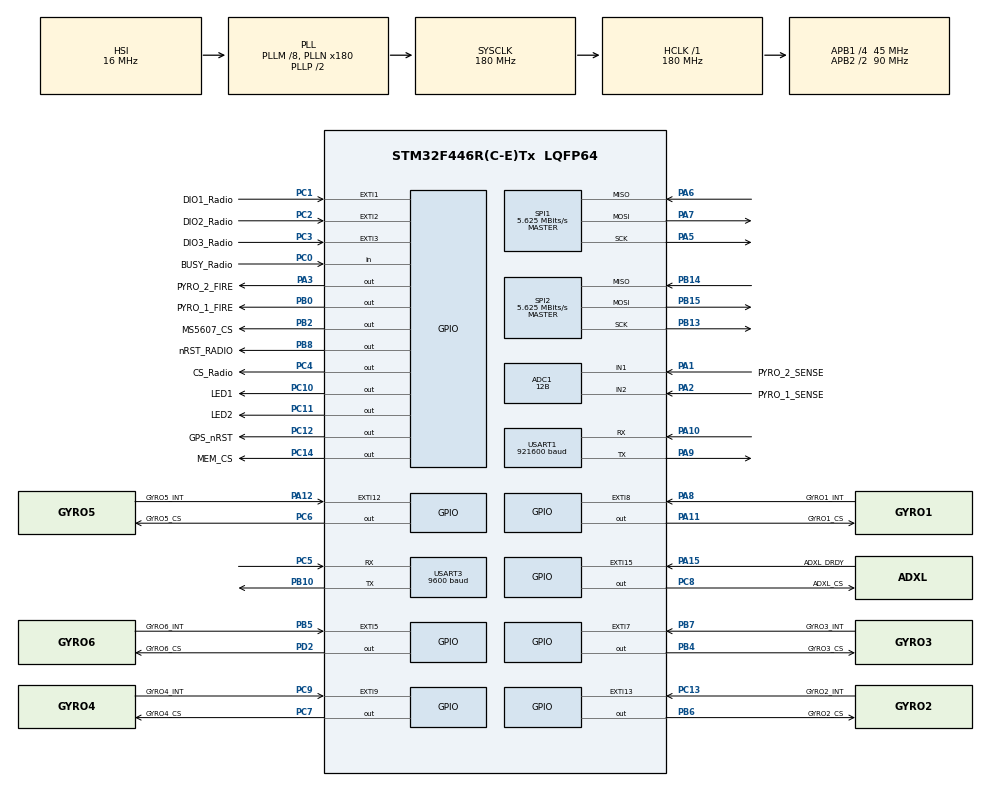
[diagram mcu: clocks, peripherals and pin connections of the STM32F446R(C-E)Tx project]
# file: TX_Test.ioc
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ADC1.Channel-0\#ChannelRegularConversion=ADC_CHANNEL_2
ADC1.ClockPrescaler=ADC_CLOCK_SYNC_PCLK_DIV4
ADC1.ContinuousConvMode=DISABLE
ADC1.DMAContinuousRequests=DISABLE
ADC1.DataAlign=ADC_DATAALIGN_RIGHT
ADC1.DiscontinuousConvMode=DISABLE
ADC1.EOCSelection=ADC_EOC_SINGLE_CONV
ADC1.EnableAnalogWatchDog=false
ADC1.ExternalTrigConv=ADC_SOFTWARE_START
ADC1.ExternalTrigConvEdge=ADC_EXTERNALTRIGCONVEDGE_NONE
ADC1.InjNumberOfConversion=0
ADC1.NbrOfConversion=1
ADC1.NbrOfConversionFlag=1
ADC1.Rank-0\#ChannelRegularConversion=1
ADC1.Resolution=ADC_RESOLUTION_12B
ADC1.SamplingTime-0\#ChannelRegularConversion=ADC_SAMPLETIME_3CYCLES
ADC1.ScanConvMode=DISABLE
ADC1.master=1
Mcu.Family=STM32F4
Mcu.Name=STM32F446R(C-E)Tx
Mcu.Package=LQFP64
NVIC.EXTI15_10_IRQn=true\:1\:0\:true\:false\:true\:true
NVIC.EXTI1_IRQn=true\:1\:0\:true\:false\:true\:true
NVIC.EXTI2_IRQn=true\:1\:0\:true\:false\:true\:true
NVIC.EXTI3_IRQn=true\:1\:0\:true\:false\:true\:true
NVIC.EXTI9_5_IRQn=true\:1\:0\:true\:false\:true\:true
NVIC.PriorityGroup=NVIC_PRIORITYGROUP_4
NVIC.TIM1_UP_TIM10_IRQn=true\:1\:0\:true\:false\:true\:true
NVIC.TIM6_DAC_IRQn=true\:1\:0\:true\:false\:true\:true
NVIC.TIM7_IRQn=true\:1\:0\:true\:false\:true\:true
NVIC.USART1_IRQn=true\:0\:0\:false\:false\:true\:true
NVIC.USART3_IRQn=true\:0\:0\:false\:false\:true\:true
PA1.GPIO_Label=PYRO_2_SENSE
PA1.Signal=ADCx_IN1
PA10.Mode=Asynchronous
PA10.Signal=USART1_RX
PA11.GPIO_Label=GYRO1_CS
PA11.GPIO_Speed=GPIO_SPEED_FREQ_HIGH
PA11.Signal=GPIO_Output
PA12.GPIO_Label=GYRO5_INT
PA12.Signal=GPXTI12
PA13.Mode=Trace_Asynchronous_SW
PA13.Signal=SYS_JTMS-SWDIO
PA14.Mode=Trace_Asynchronous_SW
PA14.Signal=SYS_JTCK-SWCLK
PA15.GPIO_Label=ADXL_DRDY
PA15.Signal=GPXTI15
PA2.GPIO_Label=PYRO_1_SENSE
PA2.Signal=ADCx_IN2
PA3.GPIO_Label=PYRO_2_FIRE
PA3.Signal=GPIO_Output
PA5.Mode=Full_Duplex_Master
PA5.Signal=SPI1_SCK
PA6.Mode=Full_Duplex_Master
PA6.Signal=SPI1_MISO
PA7.Mode=Full_Duplex_Master
PA7.Signal=SPI1_MOSI
PA8.GPIO_Label=GYRO1_INT
PA8.Signal=GPXTI8
PA9.Mode=Asynchronous
PA9.Signal=USART1_TX
PB0.GPIO_Label=PYRO_1_FIRE
PB0.Signal=GPIO_Output
PB10.Mode=Asynchronous
PB10.Signal=USART3_TX
PB13.Mode=Full_Duplex_Master
PB13.Signal=SPI2_SCK
PB14.Mode=Full_Duplex_Master
PB14.Signal=SPI2_MISO
PB15.Mode=Full_Duplex_Master
PB15.Signal=SPI2_MOSI
PB2.GPIO_Label=MS5607_CS
PB2.GPIO_Speed=GPIO_SPEED_FREQ_HIGH
PB2.Signal=GPIO_Output
PB3.Mode=Trace_Asynchronous_SW
PB3.Signal=SYS_JTDO-SWO
PB4.GPIO_Label=GYRO3_CS
PB4.GPIO_Speed=GPIO_SPEED_FREQ_HIGH
PB4.Signal=GPIO_Output
PB5.GPIO_Label=GYRO6_INT
PB5.Signal=GPXTI5
PB6.GPIO_Label=GYRO2_CS
PB6.GPIO_Speed=GPIO_SPEED_FREQ_HIGH
PB6.Signal=GPIO_Output
PB7.GPIO_Label=GYRO3_INT
PB7.Signal=GPXTI7
PB8.GPIO_Label=nRST_RADIO
PB8.Signal=GPIO_Output
PC0.GPIO_Label=BUSY_Radio
PC0.Signal=GPIO_Input
PC1.GPIO_Label=DIO1_Radio
PC1.Signal=GPXTI1
PC10.GPIO_Label=LED1
PC10.Signal=GPIO_Output
PC11.GPIO_Label=LED2
PC11.Signal=GPIO_Output
PC12.GPIO_Label=GPS_nRST
PC12.Signal=GPIO_Output
PC13.GPIO_Label=GYRO2_INT
PC13.Signal=GPXTI13
PC14-OSC32_IN.GPIO_Label=MEM_CS
PC14-OSC32_IN.GPIO_Speed=GPIO_SPEED_FREQ_LOW
PC14-OSC32_IN.Signal=GPIO_Output
PC2.GPIO_Label=DIO2_Radio
PC2.Signal=GPXTI2
PC3.GPIO_Label=DIO3_Radio
PC3.Signal=GPXTI3
PC4.GPIO_Label=CS_Radio
PC4.Signal=GPIO_Output
PC5.Mode=Asynchronous
PC5.Signal=USART3_RX
PC6.GPIO_Label=GYRO5_CS
PC6.GPIO_Speed=GPIO_SPEED_FREQ_HIGH
PC6.Signal=GPIO_Output
PC7.GPIO_Label=GYRO4_CS
PC7.GPIO_Speed=GPIO_SPEED_FREQ_HIGH
PC7.Signal=GPIO_Output
PC8.GPIO_Label=ADXL_CS
PC8.GPIO_Speed=GPIO_SPEED_FREQ_HIGH
PC8.Signal=GPIO_Output
PC9.GPIO_Label=GYRO4_INT
PC9.Signal=GPXTI9
PD2.GPIO_Label=GYRO6_CS
PD2.GPIO_Speed=GPIO_SPEED_FREQ_HIGH
PD2.Signal=GPIO_Output
ProjectManager.HeapSize=0x200
ProjectManager.StackSize=0x400
ProjectManager.TargetToolchain=TrueSTUDIO
RCC.AHBFreq_Value=180000000
RCC.APB1CLKDivider=RCC_HCLK_DIV4
RCC.APB1Freq_Value=45000000
RCC.APB1TimFreq_Value=90000000
RCC.APB2CLKDivider=RCC_HCLK_DIV2
RCC.APB2Freq_Value=90000000
RCC.APB2TimFreq_Value=180000000
RCC.CortexFreq_Value=180000000
RCC.HCLKFreq_Value=180000000
RCC.PLLM=8
RCC.PLLN=180
RCC.SYSCLKFreq_VALUE=180000000
RCC.SYSCLKSource=RCC_SYSCLKSOURCE_PLLCLK
RCC.USBFreq_Value=180000000
RCC.VCOOutputFreq_Value=360000000
SH.ADCx_IN1.0=ADC1_IN1,IN1
SH.ADCx_IN2.0=ADC1_IN2,IN2
SPI1.BaudRatePrescaler=SPI_BAUDRATEPRESCALER_16
SPI1.CalculateBaudRate=5.625 MBits/s
SPI1.Direction=SPI_DIRECTION_2LINES
SPI1.Mode=SPI_MODE_MASTER
SPI1.VirtualType=VM_MASTER
SPI2.BaudRatePrescaler=SPI_BAUDRATEPRESCALER_8
SPI2.CalculateBaudRate=5.625 MBits/s
SPI2.Direction=SPI_DIRECTION_2LINES
SPI2.Mode=SPI_MODE_MASTER
SPI2.VirtualType=VM_MASTER
TIM10.Period=999
TIM10.Prescaler=1799
TIM6.Period=99
TIM6.Prescaler=17999
TIM7.Period=499
TIM7.Prescaler=1799
USART1.BaudRate=921600
USART1.VirtualMode=VM_ASYNC
USART3.BaudRate=9600
USART3.VirtualMode=VM_ASYNC
VP_TIM10_VS_ClockSourceINT.Mode=Enable_Timer
VP_TIM6_VS_ClockSourceINT.Mode=Enable_Timer
VP_TIM7_VS_ClockSourceINT.Mode=Enable_Timer
board=TX_Test

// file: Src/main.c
/**
  ******************************************************************************
  * File Name          : main.c
  * Description        : Main program body
  ******************************************************************************
  ** This notice applies to any and all portions of this file
  * that are not between comment pairs USER CODE BEGIN and
  * USER CODE END. Other portions of this file, whether
  * inserted by the user or by software development tools
  * are owned by their respective copyright owners.
  *
  * COPYRIGHT(c) 2018 STMicroelectronics
  *
  * Redistribution and use in source and binary forms, with or without modification,
  * are permitted provided that the following conditions are met:
  *   1. Redistributions of source code must retain the above copyright notice,
  *      this list of conditions and the following disclaimer.
  *   2. Redistributions in binary form must reproduce the above copyright notice,
  *      this list of conditions and the following disclaimer in the documentation
  *      and/or other materials provided with the distribution.
  *   3. Neither the name of STMicroelectronics nor the names of its contributors
  *      may be used to endorse or promote products derived from this software
  *      without specific prior written permission.
  *
  * THIS SOFTWARE IS PROVIDED BY THE COPYRIGHT HOLDERS AND CONTRIBUTORS "AS IS"
  * AND ANY EXPRESS OR IMPLIED WARRANTIES, INCLUDING, BUT NOT LIMITED TO, THE
  * IMPLIED WARRANTIES OF MERCHANTABILITY AND FITNESS FOR A PARTICULAR PURPOSE ARE
  * DISCLAIMED. IN NO EVENT SHALL THE COPYRIGHT HOLDER OR CONTRIBUTORS BE LIABLE
  * FOR ANY DIRECT, INDIRECT, INCIDENTAL, SPECIAL, EXEMPLARY, OR CONSEQUENTIAL
  * DAMAGES (INCLUDING, BUT NOT LIMITED TO, PROCUREMENT OF SUBSTITUTE GOODS OR
  * SERVICES; LOSS OF USE, DATA, OR PROFITS; OR BUSINESS INTERRUPTION) HOWEVER
  * CAUSED AND ON ANY THEORY OF LIABILITY, WHETHER IN CONTRACT, STRICT LIABILITY,
  * OR TORT (INCLUDING NEGLIGENCE OR OTHERWISE) ARISING IN ANY WAY OUT OF THE USE
  * OF THIS SOFTWARE, EVEN IF ADVISED OF THE POSSIBILITY OF SUCH DAMAGE.
  *
  ******************************************************************************
  */

#include "main.h"
#include "stm32f4xx_hal.h"

/* USER CODE BEGIN Includes */

/*
                                                                   `-/+osyhdmmNNy`
                                                             `-/shmNmhyso+/oMMMy`
                                                         `-+hmNdy+:.`     /mMNo`
                                                     `.:smNds/.`        .yNMm:
                                             `.:+oosmmNmy+.`          .sNMNo`
                                        `-/syhs+:./hmy/`    `::     .odmms.
       ./oyyyo:`       ./oyyy+-      ./ymNyo+oo+/:+/.    ./o//+++//+oso+o++:       .:/++/:.
      :mNNNNNNNh-     /mNNNNNNmy. -odNMMN++dmmdhddd/ `:odNs/hydddmNmdddmmmmo      /ddmmmmdh/
      hNNNmsmNNNm-    hNNNmsmNNms.dNMMMM/-mNdyydmmdd-sNMMh-Ndmmmysossssssss/     -dmmmdhmmmd-
      hNNNh :NNNNh`   hNNNy /NNmm/-+oo++.dNNdd-:dmNNd-NMMo+mddd:                `ymmmd:-dmmmh`
      hNNNh  oNNNN/   hNNNy .omNNm.ddhy-+mNNNo.:sMNNNo+MN/-dmmmho+++++++/-`     +mmmmo  ommmmo
      hNNNh  `dNNNd`  hNNNy-d-dNNm/.-...dhNNh` y.mNNNN-o.  +dmmmmmmmmmmmmmh:   -dmmmh`  `hmmmd-
      hNNNh   :NNNN/  hNmmy:Ms/mdhh.:.`omdmh- .Ny:NNNdy     .+syyyyyyyydmmmd- `ymmmm:    -dmmmy`
      hNNNh    hNNNd` hmNNy:Nh.syss/``+ddmho-:mMM:odmmm/               :mmmmo /mmmmo      ommmm/
      hNNNh    -NNNNy:dmNNy:mms:yoos-.hmmdd-mMNd+.`dmmmd`  .////////::/smmmm/.dmmmh`      `hmmmd.
      hNNNh     +mNNNNNmNm+/yso.odmmyyNddN:sdo-    :mmmms  +mmmmmmmdymmmmmmo`smmmm:        -dmmms
      sddds      -ohdddhs+sdNNMy:dsyhhyydo`-        ohhhh. /hhhhhhysshhhyo- .yhhho          +yyyy.
                    ``` :NMMMMMMh:   .:`                      `.+s.
                         /mMMMMMMs                         `./hmy-
                          .omMMMMMs.`                  `./sdNNy:
                          .-./smNMMMmho+:-..``...-:/oshmMMNmo.
                           :yhysoyNMMMMMMMMMMMMMMMMMMMMNdo-
                             .+ymMMMMMMMMMMMMMMMMMMmyo:`
                                 .-+osyyhhhyyso+:.`
 */

#include "flash.h"
#include "sensors.h"
#include "commandline.h"
#include "GPS.h"
#include "radio.h"
/* USER CODE END Includes */

ADC_HandleTypeDef hadc1;

SPI_HandleTypeDef hspi1;
SPI_HandleTypeDef hspi2;

TIM_HandleTypeDef htim6;
TIM_HandleTypeDef htim7;
TIM_HandleTypeDef htim10;

UART_HandleTypeDef huart1;
UART_HandleTypeDef huart3;

/* USER CODE BEGIN PV */
/* Private variables ---------------------------------------------------------*/

//GLOBALS:
//UART Buffers
uint8_t uart1_in;
buffer uart1_buf;
uint8_t uart3_in;
buffer uart3_buf;
uint16_t packet_number = 0;

union flt{
  float f;
  uint8_t bytes[4];
};
union flt float_conv;

//Sensors Structs
baro b;
gyro gyros[6];
accel a;
extern gps_data gps;
uint32_t last_time = 0;
volatile uint8_t LOGGING_ACTIVE = 0;
uint8_t RX_PARITY = 0;
file* logfile;

//Global Flags
volatile uint8_t ADXL_Log, GYRO1_Log, GYRO2_Log, GYRO3_Log, GYRO4_Log, GYRO5_Log, GYRO6_Log, GPS_Log;
uint8_t radio_tim, baro_tim, ms_tim;
uint8_t baro_conv_state = 0;
uint8_t transmitting = 0;
/* USER CODE END PV */

void SystemClock_Config(void);
static void MX_GPIO_Init(void);
static void MX_ADC1_Init(void);
static void MX_SPI1_Init(void);
static void MX_SPI2_Init(void);
static void MX_TIM10_Init(void);
static void MX_USART1_UART_Init(void);
static void MX_USART3_UART_Init(void);
static void MX_TIM6_Init(void);
static void MX_TIM7_Init(void);

/* USER CODE BEGIN PFP */
/* Private function prototypes -----------------------------------------------*/

/* USER CODE END PFP */

int main(void)
{

  /* USER CODE BEGIN 1 */

  // Initialize uart command buffer

  /* USER CODE END 1 */

  /* MCU Configuration----------------------------------------------------------*/

  /* Reset of all peripherals, Initializes the Flash interface and the Systick. */
  HAL_Init();

  /* Configure the system clock */
  SystemClock_Config();

  /* Initialize all configured peripherals */
  MX_GPIO_Init();
  MX_ADC1_Init();
  MX_SPI1_Init();
  MX_SPI2_Init();
  MX_TIM10_Init();
  MX_USART1_UART_Init();
  MX_USART3_UART_Init();
  MX_TIM6_Init();
  MX_TIM7_Init();

  /* USER CODE BEGIN 2 */
  //Local vars
  volatile uint8_t temp_packet[23] = {0};
  volatile uint8_t radio_status;
  uint8_t radio_tim_count = 0;
  uint8_t tx_clear = 1;
  uint8_t RXData[25] = {0};
  uint8_t TXData[25] = {0};
  uint8_t status_Byte = 0;

  //Init CS pins to default state
  HAL_GPIO_WritePin(GYRO1_CS_GPIO_Port, GYRO1_CS_Pin, 1);
  HAL_GPIO_WritePin(GYRO2_CS_GPIO_Port, GYRO2_CS_Pin, 1);
  HAL_GPIO_WritePin(GYRO3_CS_GPIO_Port, GYRO3_CS_Pin, 1);
  HAL_GPIO_WritePin(GYRO4_CS_GPIO_Port, GYRO4_CS_Pin, 1);
  HAL_GPIO_WritePin(GYRO5_CS_GPIO_Port, GYRO5_CS_Pin, 1);
  HAL_GPIO_WritePin(GYRO6_CS_GPIO_Port, GYRO6_CS_Pin, 1);
  HAL_GPIO_WritePin(MS5607_CS_GPIO_Port, MS5607_CS_Pin, 1);
  HAL_GPIO_WritePin(ADXL_CS_GPIO_Port, ADXL_CS_Pin, 1);
  HAL_GPIO_WritePin(GPS_nRST_GPIO_Port, GPS_nRST_Pin, 1);
  HAL_GPIO_WritePin(MEM_CS_GPIO_Port, MEM_CS_Pin, 1);
  HAL_GPIO_WritePin(RADIO_CS_GPIO_Port, RADIO_CS_Pin, 1);

  unlock_all(); // Flash init

  //Cmd Interface Init
  buffer_init(&uart1_buf, UART_BUFFER_SIZE, 1);
  HAL_UART_Receive_IT(&huart1, &uart1_in, 1);

  //GPS UART Init
  buffer_init(&uart3_buf, UART_BUFFER_SIZE, 3);
  HAL_UART_Receive_IT(&huart3, &uart3_in, 1);

  //Gyro Init
  init_gyros();
  for(int n = 1; n <= 6; n++){
      gyros[n-1].id = n;
  }

  //Accel Init
  init_accel();

  //Baro Init
  init_baro(&b);
  D2_conv_baro(&b);
  HAL_Delay(20);

  //Radio Init
  init_radio();
  radio_resetFIFO();
  radio_initInterrupt();

  print("System Initilization Complete\n\0");

//  for(int i = 0; i<600; i++){
//      read_gyro(&gyros[0]);
//      read_accel(&a);
//      log_accel(logfile, &a);
//      log_gyro(logfile, &gyros[0]);
//      HAL_Delay(5);
//  }
//  close_log(logfile);

  //Start Timers
  HAL_TIM_Base_Init(&htim6);
  HAL_TIM_Base_Start_IT(&htim6);
  HAL_TIM_Base_Init(&htim7);
  HAL_TIM_Base_Start_IT(&htim7);
  HAL_TIM_Base_Init(&htim10);
  HAL_TIM_Base_Start_IT(&htim10);

  /* USER CODE END 2 */

  /* Infinite loop */
  while (1)
  {

  /* USER CODE BEGIN 3 */

	  parse_buffer(&uart1_buf);

	  if(HAL_GetTick() != last_time){
		  if(LOGGING_ACTIVE == 1){
			  last_time = HAL_GetTick();
			  log_time(logfile, last_time);
		  }
	  }
    //Check if a drdy interrupt has occured and fetch data
    if(ADXL_Log == 1){
        read_accel(&a);
        if(LOGGING_ACTIVE == 1){
        	 log_accel(logfile, &a);
        }
        ADXL_Log = 0;
    }
    if(GYRO1_Log == 1){
      read_gyro(&gyros[0]);
      if(LOGGING_ACTIVE == 1){
    	  log_gyro(logfile, &gyros[0]);
	  }
      GYRO1_Log = 0;
    }
    if(GYRO2_Log == 1){
      read_gyro(&gyros[1]);
      if(LOGGING_ACTIVE == 1){
		  log_gyro(logfile, &gyros[1]);
	  }
      GYRO2_Log = 0;
    }
    if(GYRO3_Log == 1){
      read_gyro(&gyros[2]);
      if(LOGGING_ACTIVE == 1){
		  log_gyro(logfile, &gyros[2]);
	  }
      GYRO3_Log = 0;
    }
    if(GYRO4_Log == 1){
      read_gyro(&gyros[3]);
      if(LOGGING_ACTIVE == 1){
		  log_gyro(logfile, &gyros[3]);
	  }
      GYRO4_Log = 0;
    }
    if(GYRO5_Log == 1){
      read_gyro(&gyros[4]);
      if(LOGGING_ACTIVE == 1){
		  log_gyro(logfile, &gyros[4]);
	  }
      GYRO5_Log = 0;
    }
    if(GYRO6_Log == 1){
      read_gyro(&gyros[5]);
      if(LOGGING_ACTIVE == 1){
		  log_gyro(logfile, &gyros[5]);
	  }
      GYRO6_Log = 0;
    }
    if(GPS_Log == 1){
    	if(LOGGING_ACTIVE == 1){
    		log_gps(logfile, &gps);
    	}
        GPS_Log = 0;
    }

    //Check timer interrupts
    if(radio_tim == 1){

        //If we are on a multiple of 10, transmitt a packet
        if(radio_tim_count == 0 || radio_tim_count == 20 || radio_tim_count == 40 || radio_tim_count == 60 || radio_tim_count == 80){

        	if(tx_clear){
        	//Send out radio packet

        		// Build status byte
        		status_Byte = 0;	// Reset
        		status_Byte |= LOGGING_ACTIVE << 7;
        		status_Byte |= RX_PARITY << 6;

        		//

			  temp_packet[1] = status_Byte; //0x0 wil be normal packet
			  temp_packet[2] = (packet_number & 0xFF);
			  temp_packet[3] = (packet_number >> 8) & 0xFF;

			  float_conv.f = gps.latitude;
			  temp_packet[4] = float_conv.bytes[0];
			  temp_packet[5] = float_conv.bytes[1];
			  temp_packet[6] = float_conv.bytes[2];
			  temp_packet[7] = float_conv.bytes[3];

			  float_conv.f = gps.longitude;
			  temp_packet[8] = float_conv.bytes[0];
			  temp_packet[9] = float_conv.bytes[1];
			  temp_packet[10] = float_conv.bytes[2];
			  temp_packet[11] = float_conv.bytes[3];

			  //Need to write function to actually get baro_alt
			  temp_packet[12] = (b.altitude) & 0xFF;
			  temp_packet[13] = (b.altitude >> 8) & 0xFF;

			  //Same as above
	  //        temp_packet[14] = (max_alt >> 8) & 0xFF;
	  //        temp_packet[15] = (max_alt) & 0xFF;

			  //Just send gyro 2 data for now. Can send avg of all channels if wanted
			  //Need to change axis to the correct one...
			  temp_packet[16] = (gyros[2].data[2]) & 0xFF;
			  temp_packet[17] = (gyros[2].data[2] >> 8) & 0xFF;

			  //Need to write function to actually calculate vel from accel
	  //        temp_packet[18] = (gyros[1].data[1] >> 8) & 0xFF;
	  //        temp_packet[19] = (gyros[1].data[1]) & 0xFF;

			  //Need to change axis to the correct one...
			  temp_packet[20] = (a.data[2]) & 0xFF;
			  temp_packet[21] = (a.data[2] >> 8) & 0xFF;
			  temp_packet[22] = (a.data[2] >> 16) & 0xFF;

			  //Do steps for transmit
			  radio_txPacket(temp_packet);
			  packet_number += 1;
        	}
        }
        else if(radio_tim_count == 10 || radio_tim_count == 30 || radio_tim_count == 50 || radio_tim_count == 70 || radio_tim_count == 90){
        	radio_RXMode();
        }
        else if(radio_tim_count == 19 || radio_tim_count == 39 || radio_tim_count == 59 || radio_tim_count == 79 || radio_tim_count == 99){
				  //read packet
				  TXData[0] = 0x7F;
				  TXData[1] = 0x00;
				  HAL_GPIO_WritePin(RADIO_CS_GPIO_Port, RADIO_CS_Pin, 0);
				  HAL_SPI_TransmitReceive(&hspi1, TXData, RXData, 3, 0xff);
				  HAL_GPIO_WritePin(RADIO_CS_GPIO_Port, RADIO_CS_Pin, 1);

				  //This is jank af because it relies on how the radio fifo handles underflow
				  //If there actually wasn't a packet received, RXData[1] and RXData[2] will be the same
				  //But if there was, the command is setup so they will add to get 255
				  //Don't use 128/127 as commands
				  if(RXData[1] + RXData[2] == 0xFF){
					//Valid command received in RXData[1]
					//Tabbing in the document is absolutly fucked

					  RX_PARITY = (RX_PARITY == 0) ? 1 : 0;
					  //Where to define commands??
					  //They are in radio.h at the moment
					  if(RXData[1] == START_LOG){
						//Start the logging
						  if(LOGGING_ACTIVE == 0){
							  logfile = new_log();
						  }
						//Set MSB of status byte to indicate logging is on

					  }
					  else if(RXData[1] == STOP_LOG){
						//Stop the logging
						if(LOGGING_ACTIVE == 1){
							close_log(logfile);
						}
						//Reset MSB of status byte to indicate logging is off

					  }
					  else if(RXData[1] == CLEAR_FILE_SYS){
						//Clear the file system
						init_fs();
					  }
				  }
				  tx_clear = 1;
				  radio_IDLEMode();
		  }

        //radio_status = RADIO_TRANSMITTING;
        radio_tim = 0;
        radio_tim_count += 1;
        if(radio_tim_count >= 100){
            radio_tim_count = 0;
        }
    }
    if(baro_tim == 1){
        //Send conversion and/or read adc
        if(baro_conv_state == 0){
            read_D2_baro(&b);
            D1_conv_baro(&b);
            baro_conv_state = 1;
        }
        else{
            read_D1_baro(&b);
            D2_conv_baro(&b);
            conv_pres_baro(&b);
            conv_alt(&b);
            if(LOGGING_ACTIVE == 1){
            	log_baro(logfile, &b);
            }
            baro_conv_state = 0;
        }
        baro_tim = 0;

        //Use this interrupt to also update radio status
        //If radio pkt sent flag is high, then radio is in IDLE
        if((radio_readInterrupt() & 0b100) != 0){
            radio_status = RADIO_IDLE;
        }
    }
  }
  /* USER CODE END 3 */

}

/** System Clock Configuration
*/
void SystemClock_Config(void)
{

  RCC_OscInitTypeDef RCC_OscInitStruct;
  RCC_ClkInitTypeDef RCC_ClkInitStruct;

    /**Configure the main internal regulator output voltage
    */
  __HAL_RCC_PWR_CLK_ENABLE();

  __HAL_PWR_VOLTAGESCALING_CONFIG(PWR_REGULATOR_VOLTAGE_SCALE1);

    /**Initializes the CPU, AHB and APB busses clocks
    */
  RCC_OscInitStruct.OscillatorType = RCC_OSCILLATORTYPE_HSI;
  RCC_OscInitStruct.HSIState = RCC_HSI_ON;
  RCC_OscInitStruct.HSICalibrationValue = 16;
  RCC_OscInitStruct.PLL.PLLState = RCC_PLL_ON;
  RCC_OscInitStruct.PLL.PLLSource = RCC_PLLSOURCE_HSI;
  RCC_OscInitStruct.PLL.PLLM = 8;
  RCC_OscInitStruct.PLL.PLLN = 180;
  RCC_OscInitStruct.PLL.PLLP = RCC_PLLP_DIV2;
  RCC_OscInitStruct.PLL.PLLQ = 2;
  RCC_OscInitStruct.PLL.PLLR = 2;
  if (HAL_RCC_OscConfig(&RCC_OscInitStruct) != HAL_OK)
  {
    _Error_Handler(__FILE__, __LINE__);
  }

    /**Activate the Over-Drive mode
    */
  if (HAL_PWREx_EnableOverDrive() != HAL_OK)
  {
    _Error_Handler(__FILE__, __LINE__);
  }

    /**Initializes the CPU, AHB and APB busses clocks
    */
  RCC_ClkInitStruct.ClockType = RCC_CLOCKTYPE_HCLK|RCC_CLOCKTYPE_SYSCLK
                              |RCC_CLOCKTYPE_PCLK1|RCC_CLOCKTYPE_PCLK2;
  RCC_ClkInitStruct.SYSCLKSource = RCC_SYSCLKSOURCE_PLLCLK;
  RCC_ClkInitStruct.AHBCLKDivider = RCC_SYSCLK_DIV1;
  RCC_ClkInitStruct.APB1CLKDivider = RCC_HCLK_DIV4;
  RCC_ClkInitStruct.APB2CLKDivider = RCC_HCLK_DIV2;

  if (HAL_RCC_ClockConfig(&RCC_ClkInitStruct, FLASH_LATENCY_5) != HAL_OK)
  {
    _Error_Handler(__FILE__, __LINE__);
  }

    /**Configure the Systick interrupt time
    */
  HAL_SYSTICK_Config(HAL_RCC_GetHCLKFreq()/1000);

    /**Configure the Systick
    */
  HAL_SYSTICK_CLKSourceConfig(SYSTICK_CLKSOURCE_HCLK);

  /* SysTick_IRQn interrupt configuration */
  HAL_NVIC_SetPriority(SysTick_IRQn, 0, 0);
}

/* ADC1 init function */
static void MX_ADC1_Init(void)
{

  ADC_ChannelConfTypeDef sConfig;

    /**Configure the global features of the ADC (Clock, Resolution, Data Alignment and number of conversion)
    */
  hadc1.Instance = ADC1;
  hadc1.Init.ClockPrescaler = ADC_CLOCK_SYNC_PCLK_DIV4;
  hadc1.Init.Resolution = ADC_RESOLUTION_12B;
  hadc1.Init.ScanConvMode = DISABLE;
  hadc1.Init.ContinuousConvMode = DISABLE;
  hadc1.Init.DiscontinuousConvMode = DISABLE;
  hadc1.Init.ExternalTrigConvEdge = ADC_EXTERNALTRIGCONVEDGE_NONE;
  hadc1.Init.ExternalTrigConv = ADC_SOFTWARE_START;
  hadc1.Init.DataAlign = ADC_DATAALIGN_RIGHT;
  hadc1.Init.NbrOfConversion = 1;
  hadc1.Init.DMAContinuousRequests = DISABLE;
  hadc1.Init.EOCSelection = ADC_EOC_SINGLE_CONV;
  if (HAL_ADC_Init(&hadc1) != HAL_OK)
  {
    _Error_Handler(__FILE__, __LINE__);
  }

    /**Configure for the selected ADC regular channel its corresponding rank in the sequencer and its sample time.
    */
  sConfig.Channel = ADC_CHANNEL_2;
  sConfig.Rank = 1;
  sConfig.SamplingTime = ADC_SAMPLETIME_3CYCLES;
  if (HAL_ADC_ConfigChannel(&hadc1, &sConfig) != HAL_OK)
  {
    _Error_Handler(__FILE__, __LINE__);
  }

}

/* SPI1 init function */
static void MX_SPI1_Init(void)
{

  /* SPI1 parameter configuration*/
  hspi1.Instance = SPI1;
  hspi1.Init.Mode = SPI_MODE_MASTER;
  hspi1.Init.Direction = SPI_DIRECTION_2LINES;
  hspi1.Init.DataSize = SPI_DATASIZE_8BIT;
  hspi1.Init.CLKPolarity = SPI_POLARITY_LOW;
  hspi1.Init.CLKPhase = SPI_PHASE_1EDGE;
  hspi1.Init.NSS = SPI_NSS_SOFT;
  hspi1.Init.BaudRatePrescaler = SPI_BAUDRATEPRESCALER_16;
  hspi1.Init.FirstBit = SPI_FIRSTBIT_MSB;
  hspi1.Init.TIMode = SPI_TIMODE_DISABLE;
  hspi1.Init.CRCCalculation = SPI_CRCCALCULATION_DISABLE;
  hspi1.Init.CRCPolynomial = 10;
  if (HAL_SPI_Init(&hspi1) != HAL_OK)
  {
    _Error_Handler(__FILE__, __LINE__);
  }

}

/* SPI2 init function */
static void MX_SPI2_Init(void)
{

  /* SPI2 parameter configuration*/
  hspi2.Instance = SPI2;
  hspi2.Init.Mode = SPI_MODE_MASTER;
  hspi2.Init.Direction = SPI_DIRECTION_2LINES;
  hspi2.Init.DataSize = SPI_DATASIZE_8BIT;
  hspi2.Init.CLKPolarity = SPI_POLARITY_LOW;
  hspi2.Init.CLKPhase = SPI_PHASE_1EDGE;
  hspi2.Init.NSS = SPI_NSS_SOFT;
  hspi2.Init.BaudRatePrescaler = SPI_BAUDRATEPRESCALER_8;
  hspi2.Init.FirstBit = SPI_FIRSTBIT_MSB;
  hspi2.Init.TIMode = SPI_TIMODE_DISABLE;
  hspi2.Init.CRCCalculation = SPI_CRCCALCULATION_DISABLE;
  hspi2.Init.CRCPolynomial = 10;
  if (HAL_SPI_Init(&hspi2) != HAL_OK)
  {
    _Error_Handler(__FILE__, __LINE__);
  }

}

/* TIM6 init function */
static void MX_TIM6_Init(void)
{

  TIM_MasterConfigTypeDef sMasterConfig;

  htim6.Instance = TIM6;
  htim6.Init.Prescaler = 17999;
  htim6.Init.CounterMode = TIM_COUNTERMODE_UP;
  htim6.Init.Period = 99;
  if (HAL_TIM_Base_Init(&htim6) != HAL_OK)
  {
    _Error_Handler(__FILE__, __LINE__);
  }

  sMasterConfig.MasterOutputTrigger = TIM_TRGO_RESET;
  sMasterConfig.MasterSlaveMode = TIM_MASTERSLAVEMODE_DISABLE;
  if (HAL_TIMEx_MasterConfigSynchronization(&htim6, &sMasterConfig) != HAL_OK)
  {
    _Error_Handler(__FILE__, __LINE__);
  }

}

/* TIM7 init function */
static void MX_TIM7_Init(void)
{

  TIM_MasterConfigTypeDef sMasterConfig;

  htim7.Instance = TIM7;
  htim7.Init.Prescaler = 1799;
  htim7.Init.CounterMode = TIM_COUNTERMODE_UP;
  htim7.Init.Period = 499;
  if (HAL_TIM_Base_Init(&htim7) != HAL_OK)
  {
    _Error_Handler(__FILE__, __LINE__);
  }

  sMasterConfig.MasterOutputTrigger = TIM_TRGO_RESET;
  sMasterConfig.MasterSlaveMode = TIM_MASTERSLAVEMODE_DISABLE;
  if (HAL_TIMEx_MasterConfigSynchronization(&htim7, &sMasterConfig) != HAL_OK)
  {
    _Error_Handler(__FILE__, __LINE__);
  }

}

/* TIM10 init function */
static void MX_TIM10_Init(void)
{

  htim10.Instance = TIM10;
  htim10.Init.Prescaler = 1799;
  htim10.Init.CounterMode = TIM_COUNTERMODE_UP;
  htim10.Init.Period = 999;
  htim10.Init.ClockDivision = TIM_CLOCKDIVISION_DIV1;
  if (HAL_TIM_Base_Init(&htim10) != HAL_OK)
  {
    _Error_Handler(__FILE__, __LINE__);
  }

}

/* USART1 init function */
static void MX_USART1_UART_Init(void)
{

  huart1.Instance = USART1;
  huart1.Init.BaudRate = 921600;
  huart1.Init.WordLength = UART_WORDLENGTH_8B;
  huart1.Init.StopBits = UART_STOPBITS_1;
  huart1.Init.Parity = UART_PARITY_NONE;
  huart1.Init.Mode = UART_MODE_TX_RX;
  huart1.Init.HwFlowCtl = UART_HWCONTROL_NONE;
  huart1.Init.OverSampling = UART_OVERSAMPLING_16;
  if (HAL_UART_Init(&huart1) != HAL_OK)
  {
    _Error_Handler(__FILE__, __LINE__);
  }

}

/* USART3 init function */
static void MX_USART3_UART_Init(void)
{

  huart3.Instance = USART3;
  huart3.Init.BaudRate = 9600;
  huart3.Init.WordLength = UART_WORDLENGTH_8B;
  huart3.Init.StopBits = UART_STOPBITS_1;
  huart3.Init.Parity = UART_PARITY_NONE;
  huart3.Init.Mode = UART_MODE_TX_RX;
  huart3.Init.HwFlowCtl = UART_HWCONTROL_NONE;
  huart3.Init.OverSampling = UART_OVERSAMPLING_16;
  if (HAL_UART_Init(&huart3) != HAL_OK)
  {
    _Error_Handler(__FILE__, __LINE__);
  }

}

/** Configure pins as
        * Analog
        * Input
        * Output
        * EVENT_OUT
        * EXTI
*/
static void MX_GPIO_Init(void)
{

  GPIO_InitTypeDef GPIO_InitStruct;

  /* GPIO Ports Clock Enable */
  __HAL_RCC_GPIOC_CLK_ENABLE();
  __HAL_RCC_GPIOA_CLK_ENABLE();
  __HAL_RCC_GPIOB_CLK_ENABLE();
  __HAL_RCC_GPIOD_CLK_ENABLE();

  /*Configure GPIO pin Output Level */
  HAL_GPIO_WritePin(GPIOC, MEM_CS_Pin|PYRO_2_FIRE_Pin|GYRO5_CS_Pin|GYRO4_CS_Pin
                          |ADXL_CS_Pin|RADIO_CS_Pin|GPS_nRST_Pin, GPIO_PIN_RESET);

  /*Configure GPIO pin Output Level */
  HAL_GPIO_WritePin(GPIOA, PYRO_1_FIRE_Pin|GYRO1_CS_Pin, GPIO_PIN_RESET);

  /*Configure GPIO pin Output Level */
  HAL_GPIO_WritePin(GPIOB, MS5607_CS_Pin|GYRO3_CS_Pin|GYRO2_CS_Pin, GPIO_PIN_RESET);

  /*Configure GPIO pin Output Level */
  HAL_GPIO_WritePin(GYRO6_CS_GPIO_Port, GYRO6_CS_Pin, GPIO_PIN_RESET);

  /*Configure GPIO pins : GYRO2_INT_Pin GYRO4_INT_Pin nIRQ_RADIO_Pin */
  GPIO_InitStruct.Pin = GYRO2_INT_Pin|GYRO4_INT_Pin|nIRQ_RADIO_Pin;
  GPIO_InitStruct.Mode = GPIO_MODE_IT_RISING;
  GPIO_InitStruct.Pull = GPIO_NOPULL;
  HAL_GPIO_Init(GPIOC, &GPIO_InitStruct);

  /*Configure GPIO pins : MEM_CS_Pin PYRO_2_FIRE_Pin GPS_nRST_Pin */
  GPIO_InitStruct.Pin = MEM_CS_Pin|PYRO_2_FIRE_Pin|GPS_nRST_Pin;
  GPIO_InitStruct.Mode = GPIO_MODE_OUTPUT_PP;
  GPIO_InitStruct.Pull = GPIO_NOPULL;
  GPIO_InitStruct.Speed = GPIO_SPEED_FREQ_LOW;
  HAL_GPIO_Init(GPIOC, &GPIO_InitStruct);

  /*Configure GPIO pin : PYRO_1_FIRE_Pin */
  GPIO_InitStruct.Pin = PYRO_1_FIRE_Pin;
  GPIO_InitStruct.Mode = GPIO_MODE_OUTPUT_PP;
  GPIO_InitStruct.Pull = GPIO_NOPULL;
  GPIO_InitStruct.Speed = GPIO_SPEED_FREQ_LOW;
  HAL_GPIO_Init(PYRO_1_FIRE_GPIO_Port, &GPIO_InitStruct);

  /*Configure GPIO pins : MS5607_CS_Pin GYRO3_CS_Pin GYRO2_CS_Pin */
  GPIO_InitStruct.Pin = MS5607_CS_Pin|GYRO3_CS_Pin|GYRO2_CS_Pin;
  GPIO_InitStruct.Mode = GPIO_MODE_OUTPUT_PP;
  GPIO_InitStruct.Pull = GPIO_NOPULL;
  GPIO_InitStruct.Speed = GPIO_SPEED_FREQ_HIGH;
  HAL_GPIO_Init(GPIOB, &GPIO_InitStruct);

  /*Configure GPIO pins : GYRO5_CS_Pin GYRO4_CS_Pin ADXL_CS_Pin RADIO_CS_Pin */
  GPIO_InitStruct.Pin = GYRO5_CS_Pin|GYRO4_CS_Pin|ADXL_CS_Pin|RADIO_CS_Pin;
  GPIO_InitStruct.Mode = GPIO_MODE_OUTPUT_PP;
  GPIO_InitStruct.Pull = GPIO_NOPULL;
  GPIO_InitStruct.Speed = GPIO_SPEED_FREQ_HIGH;
  HAL_GPIO_Init(GPIOC, &GPIO_InitStruct);

  /*Configure GPIO pins : GYRO1_INT_Pin GYRO5_INT_Pin ADXL_DRDY_Pin */
  GPIO_InitStruct.Pin = GYRO1_INT_Pin|GYRO5_INT_Pin|ADXL_DRDY_Pin;
  GPIO_InitStruct.Mode = GPIO_MODE_IT_RISING;
  GPIO_InitStruct.Pull = GPIO_NOPULL;
  HAL_GPIO_Init(GPIOA, &GPIO_InitStruct);

  /*Configure GPIO pin : GYRO1_CS_Pin */
  GPIO_InitStruct.Pin = GYRO1_CS_Pin;
  GPIO_InitStruct.Mode = GPIO_MODE_OUTPUT_PP;
  GPIO_InitStruct.Pull = GPIO_NOPULL;
  GPIO_InitStruct.Speed = GPIO_SPEED_FREQ_HIGH;
  HAL_GPIO_Init(GYRO1_CS_GPIO_Port, &GPIO_InitStruct);

  /*Configure GPIO pin : GYRO6_CS_Pin */
  GPIO_InitStruct.Pin = GYRO6_CS_Pin;
  GPIO_InitStruct.Mode = GPIO_MODE_OUTPUT_PP;
  GPIO_InitStruct.Pull = GPIO_NOPULL;
  GPIO_InitStruct.Speed = GPIO_SPEED_FREQ_HIGH;
  HAL_GPIO_Init(GYRO6_CS_GPIO_Port, &GPIO_InitStruct);

  /*Configure GPIO pins : GYRO6_INT_Pin GYRO3_INT_Pin */
  GPIO_InitStruct.Pin = GYRO6_INT_Pin|GYRO3_INT_Pin;
  GPIO_InitStruct.Mode = GPIO_MODE_IT_RISING;
  GPIO_InitStruct.Pull = GPIO_NOPULL;
  HAL_GPIO_Init(GPIOB, &GPIO_InitStruct);

  /* EXTI interrupt init*/
  HAL_NVIC_SetPriority(EXTI9_5_IRQn, 1, 0);
  HAL_NVIC_EnableIRQ(EXTI9_5_IRQn);

  HAL_NVIC_SetPriority(EXTI15_10_IRQn, 1, 0);
  HAL_NVIC_EnableIRQ(EXTI15_10_IRQn);

}

void _Error_Handler(char * file, int line)
{
  while(1)
  {
  }
}

/************************ (C) COPYRIGHT STMicroelectronics *****END OF FILE****/
